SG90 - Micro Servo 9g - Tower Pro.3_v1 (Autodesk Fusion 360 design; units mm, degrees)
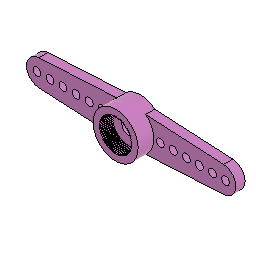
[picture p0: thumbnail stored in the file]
part number: SG90 - Micro Servo 9g - Tower Pro.3
base_feature "Base Feature"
